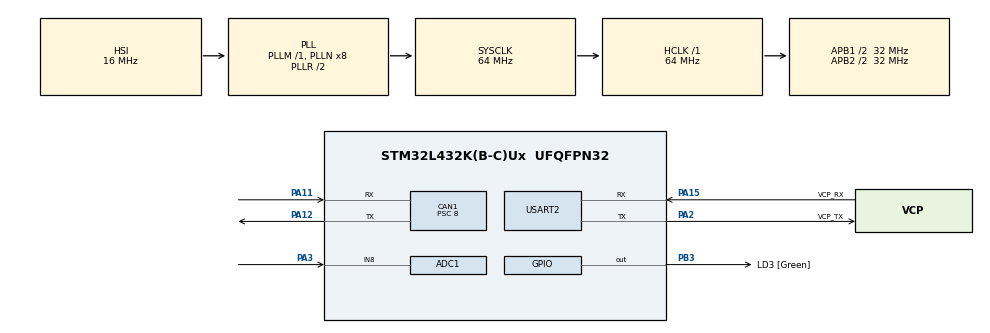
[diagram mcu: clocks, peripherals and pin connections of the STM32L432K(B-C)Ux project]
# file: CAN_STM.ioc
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ADC1.Channel-0\#ChannelRegularConversion=ADC_CHANNEL_8
ADC1.NbrOfConversionFlag=1
ADC1.OffsetNumber-0\#ChannelRegularConversion=ADC_OFFSET_NONE
ADC1.Rank-0\#ChannelRegularConversion=1
ADC1.SamplingTime-0\#ChannelRegularConversion=ADC_SAMPLETIME_2CYCLES_5
ADC1.master=1
CAN1.BS1=CAN_BS1_4TQ
CAN1.BS2=CAN_BS2_3TQ
CAN1.CalculateBaudRate=500000
CAN1.CalculateTimeBit=2000
CAN1.CalculateTimeQuantum=250.0
CAN1.Prescaler=8
Mcu.Family=STM32L4
Mcu.Name=STM32L432K(B-C)Ux
Mcu.Package=UFQFPN32
NVIC.CAN1_RX0_IRQn=true\:0\:0\:false\:false\:true\:true\:true\:true
NVIC.CAN1_RX1_IRQn=true\:0\:0\:false\:false\:true\:true\:true\:true
NVIC.PriorityGroup=NVIC_PRIORITYGROUP_4
NVIC.TIM6_DAC_IRQn=true\:0\:0\:false\:false\:true\:true\:true\:true
PA0.GPIO_Label=MCO [High speed clock in]
PA0.Mode=HSE-External-Clock-Source-for-LittleOrca
PA0.Signal=RCC_CK_IN
PA11.Mode=CAN_Activate
PA11.Signal=CAN1_RX
PA12.Mode=CAN_Activate
PA12.Signal=CAN1_TX
PA13\ (JTMS-SWDIO).GPIO_Label=SWDIO
PA13\ (JTMS-SWDIO).Mode=Serial_Wire
PA13\ (JTMS-SWDIO).Signal=SYS_JTMS-SWDIO
PA14\ (JTCK-SWCLK).GPIO_Label=SWCLK
PA14\ (JTCK-SWCLK).Mode=Serial_Wire
PA14\ (JTCK-SWCLK).Signal=SYS_JTCK-SWCLK
PA15\ (JTDI).GPIO_Label=VCP_RX
PA15\ (JTDI).Mode=Asynchronous
PA15\ (JTDI).Signal=USART2_RX
PA2.GPIO_Label=VCP_TX
PA2.Mode=Asynchronous
PA2.Signal=USART2_TX
PA3.Signal=ADCx_IN8
PB3\ (JTDO-TRACESWO).GPIO_Label=LD3 [Green]
PB3\ (JTDO-TRACESWO).Signal=GPIO_Output
PC14-OSC32_IN\ (PC14).Mode=LSE-External-Oscillator
PC14-OSC32_IN\ (PC14).Signal=RCC_OSC32_IN
PC15-OSC32_OUT\ (PC15).Mode=LSE-External-Oscillator
PC15-OSC32_OUT\ (PC15).Signal=RCC_OSC32_OUT
ProjectManager.HeapSize=0x200
ProjectManager.StackSize=0x400
ProjectManager.TargetToolchain=STM32CubeIDE
RCC.ADCFreq_Value=64000000
RCC.AHBFreq_Value=64000000
RCC.APB1CLKDivider=RCC_HCLK_DIV2
RCC.APB1Freq_Value=32000000
RCC.APB1TimFreq_Value=64000000
RCC.APB2CLKDivider=RCC_HCLK_DIV2
RCC.APB2Freq_Value=32000000
RCC.APB2TimFreq_Value=64000000
RCC.CortexFreq_Value=64000000
RCC.HCLKFreq_Value=64000000
RCC.HSE_VALUE=24000000
RCC.HSI16_VALUE=16000000
RCC.HSI48_VALUE=48000000
RCC.HSI_VALUE=16000000
RCC.MSI_VALUE=4000000
RCC.PLLMUL=RCC_PLLMUL_4
RCC.PLLSourceVirtual=RCC_PLLSOURCE_HSI
RCC.SYSCLKFreq_VALUE=64000000
RCC.SYSCLKSource=RCC_SYSCLKSOURCE_PLLCLK
RCC.USBFreq_Value=64000000
RCC.VCOOutputFreq_Value=128000000
SH.ADCx_IN8.0=ADC1_IN8,IN8-Single-Ended
TIM6.AutoReloadPreload=TIM_AUTORELOAD_PRELOAD_ENABLE
TIM6.Period=10000
TIM6.Prescaler=6400
USART2.VirtualMode-Asynchronous=VM_ASYNC
VP_TIM6_VS_ClockSourceINT.Mode=Enable_Timer
board=NUCLEO-L432KC

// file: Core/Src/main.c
/* USER CODE BEGIN Header */
/**
  ******************************************************************************
  * @file           : main.c
  * @brief          : Main program body
  ******************************************************************************
  * @attention
  *
  * Copyright (c) 2023 STMicroelectronics.
  * All rights reserved.
  *
  * This software is licensed under terms that can be found in the LICENSE file
  * in the root directory of this software component.
  * If no LICENSE file comes with this software, it is provided AS-IS.
  *
  ******************************************************************************
  */
/* USER CODE END Header */
#include "main.h"

/* USER CODE BEGIN PTD */
#include <stdio.h>
#include <string.h>
#include "mia.h"
/* USER CODE END PTD */

/* USER CODE BEGIN PD */

#define CAN_VAR_STAT
/* USER CODE END PD */

/* USER CODE BEGIN PM */

/* Private variables ---------------------------------------------------------*/
ADC_HandleTypeDef hadc1;

CAN_HandleTypeDef hcan1;

TIM_HandleTypeDef htim6;

UART_HandleTypeDef huart2;

/* USER CODE BEGIN PV */

uint16_t swap_endianness(uint16_t value) //Zrob implementacje dla inta?
{
    uint16_t ret_val;
    uint8_t lsb, msb;
    lsb = value & 0x00FF;
    msb = value & 0xFF00;
    ret_val = (lsb << 8) + (msb >> 8);

    return ret_val;

}

uint16_t asym_constraint(uint16_t value, uint16_t max)
{
    if(value > max)
    {
        return max;
    }
    else
    {
        return value;
    }
}

/* USER CODE END PM */

typedef struct __attribute__((__packed__)) stat
{
    int32_t motor_speed;
    int16_t motor_torque;
    int16_t status_word;
}stat_t;
typedef struct  __attribute__((__packed__)) CAN_EGV_Accel_VAR
{
    uint16_t accelerator_set_point;//little endian
    uint16_t regen_max;
    unsigned int forward : 1 ;
    unsigned int reverse : 1 ;
    unsigned int footbrake : 1;
    unsigned int DS1 : 1 ;
    unsigned int footswitch :1;
    unsigned int DS2 : 1;
    unsigned int unused :2;

} CAN_EGV_Accel_VAR_t;

typedef struct __attribute__((__packed__))  CAN_EGV_Cmd_VAR
{
    int16_t current_limit; //0 to 500
    int16_t regen_limit;
    uint16_t max_torque_ratio;
    uint16_t motor_command;

} CAN_EGV_Cmd_VAR_t;

typedef struct __attribute__((__packed__))  CAN_BMS_CHA
{
    int16_t charging_current; //0 to 500
    int16_t max_voltage;
    uint8_t status;

} CAN_BMS_CHA_t;

typedef struct CAN_EGV_SYNC_ALL
{
uint8_t status;

} CAN_EGV_SYNC_ALL_t;

void can_send_egv_sync_all(CAN_EGV_SYNC_ALL_t * frame)
{
    CAN_TxHeaderTypeDef carrier = {0};
    carrier.StdId = CAN_EGV_SYNC_ALL_ID;
    carrier.DLC = sizeof (CAN_EGV_SYNC_ALL_t);
    HAL_CAN_AddTxMessage(&hcan1,&carrier,(char*)frame,NULL);

}

void can_send_egv_accel_var(CAN_EGV_Accel_VAR_t * frame)
{
    CAN_TxHeaderTypeDef carrier = {0};

    carrier.StdId = CAN_EGV_ACCEL_VAR_ID;
    carrier.DLC = sizeof (CAN_EGV_Accel_VAR_t);
    //frame->accelerator_set_point = swap_endianness(frame->accelerator_set_point);
    HAL_CAN_AddTxMessage(&hcan1,&carrier,(char *)frame,NULL);
}

void can_send_egv_cmd_var(CAN_EGV_Cmd_VAR_t * frame)
{
    CAN_TxHeaderTypeDef carrier = {0};

    CAN_EGV_Cmd_VAR_t payload;

    carrier.StdId = CAN_EGV_CMD_VAR_ID;
    carrier.DLC = sizeof (CAN_EGV_Cmd_VAR_t);

    frame->regen_limit = swap_endianness(    frame->regen_limit);
    frame->max_torque_ratio = swap_endianness(frame->max_torque_ratio);
    frame->current_limit = swap_endianness(frame->current_limit);
    frame->motor_command = 0;
    frame->motor_command = swap_endianness(frame->current_limit);
    HAL_CAN_AddTxMessage(&hcan1,&carrier,(char *)&frame,NULL);

}

void can_bms_cha(CAN_BMS_CHA_t * frame)
{
    CAN_TxHeaderTypeDef carrier = {0};

    carrier.StdId = CAN_BMS_CHA_ID;
    carrier.DLC = 6;
    uint8_t crap[6];
    crap[0]=0xc8;
    crap[1]=0x00;
    crap[2]=0x88;
    crap[3]=0x13;
    crap[4]=0x03;
    crap[5]=0x00;
    //frame->accelerator_set_point = sw,ap_endianness(frame->accelerator_set_point);
    HAL_CAN_AddTxMessage(&hcan1,&carrier,(char *)frame,NULL);
}

uint16_t get_throttle()
{
    HAL_ADC_Start(&hadc1);
    uint32_t reading = HAL_ADC_GetValue(&hadc1); //0-4096
    reading = (reading>>4); //0 - 255

    if(reading > MIN_RAW_ADC_ACCEL)
    {
        reading = asym_constraint((reading-MIN_RAW_ADC_ACCEL)*250/200 + MIN_THROTTLE,MAX_RAW_ADC_ACCEL);
    }
    else
    {
        reading = 0;
    }
    return (uint16_t)reading;
}

volatile car_t mia;

void update_accel_pedal(CAN_EGV_Accel_VAR_t * frame)
{
    //int direction_forward = (HAL_GPIO_ReadPin(GPIOA, GPIO_PIN_4)== GPIO_PIN_SET);
    int direction_forward = !mia.in_reverse;

    uint16_t throttle = get_throttle();

    if(mia.var_ready && throttle >= (MIN_THROTTLE) )
    {
        frame->accelerator_set_point = throttle;
        frame->footswitch = 1; //?
        frame->unused = 0;
        frame->regen_max = 0;
        frame->footbrake =0;

        if(direction_forward)
        {
            frame->reverse = 0;
            frame->forward = 1;
        } else
        {
            frame->reverse=1;
            frame->forward = 0;
        }
    } else
    {
        frame->footswitch = 0;
        frame->forward = 0;
        frame->reverse = 0;
        frame->accelerator_set_point = 0;
    }
}

volatile CAN_EGV_Accel_VAR_t egv_accel_frame ={0};

volatile CAN_EGV_SYNC_ALL_t egv_sync_frame ={0};

volatile CAN_EGV_Cmd_VAR_t egv_var_frame ={0};

volatile CAN_BMS_CHA_t bms_cha_frame = {0};

stat_t var_stat;

void diagnostics_print()
{
    printf("Var stat: %d\nvar status %d:", var_stat.motor_speed, var_stat.status_word);
    printf("Accel frame 0x201: \n");
    printf("Accel var values %d", egv_accel_frame);
    printf("accel setpoint: %d \nfootswitch: %d \nforward: %d \n\n" ,egv_accel_frame.accelerator_set_point, egv_accel_frame.footswitch, egv_accel_frame.forward);
}

/* USER CODE END PV */
void SystemClock_Config(void);
static void MX_GPIO_Init(void);
static void MX_USART2_UART_Init(void);
static void MX_CAN1_Init(void);
static void MX_ADC1_Init(void);
static void MX_TIM6_Init(void);

/* USER CODE BEGIN 0 */
void HAL_TIM_PeriodElapsedCallback(TIM_HandleTypeDef * htim)
{

    update_accel_pedal(&egv_accel_frame);
    can_send_egv_sync_all(&egv_sync_frame);
    can_send_egv_accel_var(&egv_accel_frame);
    can_send_egv_cmd_var(&can_send_egv_cmd_var);

}

void HAL_CAN_RxFIFO0MsgPendingCallback(CAN_HandleTypeDef *hcan)
{
    //HAL_GPIO_TogglePin(LD3_GPIO_Port,LD3_Pin);
}

int __io_putchar(int ch)
{
    if (ch == '\n') {
        uint8_t ch2 = '\r';
        HAL_UART_Transmit(&huart2, &ch2, 1, HAL_MAX_DELAY);
    }

    HAL_UART_Transmit(&huart2, (uint8_t*)&ch, 1, HAL_MAX_DELAY);
    return 1;
}
/* USER CODE END 0 */

int main(void)
{

  /* MCU Configuration--------------------------------------------------------*/

  /* Reset of all peripherals, Initializes the Flash interface and the Systick. */
  HAL_Init();

  /* Configure the system clock */
  SystemClock_Config();

  /* USER CODE BEGIN SysInit */

  mia.in_reverse = 0;
  mia.reverse_button_pressed=0;
  egv_accel_frame;

  egv_accel_frame.accelerator_set_point = 0;
  egv_accel_frame.footbrake=0;
  egv_accel_frame.footswitch = 0; //?
  egv_accel_frame.regen_max = 0;
  egv_accel_frame.forward = 0;

  egv_sync_frame.status =0xff;

  egv_var_frame.current_limit = 0;
  egv_var_frame.max_torque_ratio =0;
  egv_var_frame.motor_command = 0;
  egv_var_frame.regen_limit = 0;

  bms_cha_frame.max_voltage = 8000;
  bms_cha_frame.charging_current = 550;
  bms_cha_frame.status = 1+2;
  /* USER CODE END SysInit */

  /* Initialize all configured peripherals */
  MX_GPIO_Init();
  MX_USART2_UART_Init();
  MX_CAN1_Init();
  MX_ADC1_Init();
  MX_TIM6_Init();
  /* USER CODE BEGIN 2 */

    __HAL_RCC_TIM6_CLK_ENABLE();
    HAL_TIM_Base_Start_IT(&htim6);
    HAL_NVIC_EnableIRQ(TIM6_IRQn);
    HAL_NVIC_EnableIRQ(CAN1_RX0_IRQn);

    CAN_FilterTypeDef sFilterConfig;

    sFilterConfig.FilterFIFOAssignment=CAN_FILTER_FIFO0; //set fifo assignment
    sFilterConfig.FilterIdHigh=0x181<<5; //the ID that the filter looks for (switch this for the other microcontroller)
    sFilterConfig.FilterIdLow=0;
    sFilterConfig.FilterMaskIdHigh=0;
    sFilterConfig.FilterMaskIdLow=0;
    sFilterConfig.FilterScale=CAN_FILTERSCALE_32BIT; //set filter scale
    sFilterConfig.FilterActivation=ENABLE;

    HAL_CAN_ConfigFilter(&hcan1, &sFilterConfig); //configure CAN filter

//
    HAL_CAN_Start(&hcan1);
    HAL_CAN_ActivateNotification(&hcan1, CAN_IT_RX_FIFO0_MSG_PENDING);

    __HAL_RCC_ADC_CLK_ENABLE();
    HAL_ADC_Start(&hadc1);

    HAL_Delay(1000);
    HAL_GPIO_WritePin(GPIOB,GPIO_PIN_7,GPIO_PIN_SET);
  /* USER CODE END 2 */

  /* Infinite loop */
  while (1)
  {

    /* USER CODE BEGIN 3 */
      diagnostics_print();
      if(var_stat.status_word == 1075)
    {
        mia.var_ready =1;
        egv_var_frame.current_limit = 400; //2640
        egv_var_frame.regen_limit =-20;
        egv_var_frame.max_torque_ratio =1000;
        egv_accel_frame.footswitch=1;
    }
      volatile uint8_t button_state = 0;
      if(HAL_GPIO_ReadPin(GPIOA, GPIO_PIN_4)== GPIO_PIN_RESET)
      {
          button_state = 1;
          mia.in_reverse = 1;
      }
      else
      {
          mia.in_reverse = 0;
      }
//
//      if(mia.reverse_button_pressed == 0 && button_state == 1) {
//          car_toggle_gear(&mia);
//         // mia.reverse_button_pressed = !mia.reverse_button_pressed;
//         mia.reverse_button_pressed = 1;
//      }
//      if(button_state == 0)
//      {
//          mia.reverse_button_pressed = 0;
//      }
//      if(button_state == 1)
//      {
//          mia.reverse_button_pressed =1;
//      }

     HAL_Delay(1000);
      HAL_GPIO_TogglePin(LD3_GPIO_Port,LD3_Pin);
      can_bms_cha(&bms_cha_frame);
      printf("%d \n",egv_accel_frame.accelerator_set_point);

  }
  /* USER CODE END 3 */

}

void SystemClock_Config(void)
{
  RCC_OscInitTypeDef RCC_OscInitStruct = {0};
  RCC_ClkInitTypeDef RCC_ClkInitStruct = {0};

  /** Configure the main internal regulator output voltage
  */
  if (HAL_PWREx_ControlVoltageScaling(PWR_REGULATOR_VOLTAGE_SCALE1) != HAL_OK)
  {
    Error_Handler();
  }

  /** Initializes the RCC Oscillators according to the specified parameters
  * in the RCC_OscInitTypeDef structure.
  */
  RCC_OscInitStruct.OscillatorType = RCC_OSCILLATORTYPE_HSI;
  RCC_OscInitStruct.HSIState = RCC_HSI_ON;
  RCC_OscInitStruct.HSICalibrationValue = RCC_HSICALIBRATION_DEFAULT;
  RCC_OscInitStruct.PLL.PLLState = RCC_PLL_ON;
  RCC_OscInitStruct.PLL.PLLSource = RCC_PLLSOURCE_HSI;
  RCC_OscInitStruct.PLL.PLLM = 1;
  RCC_OscInitStruct.PLL.PLLN = 8;
  RCC_OscInitStruct.PLL.PLLP = RCC_PLLP_DIV7;
  RCC_OscInitStruct.PLL.PLLQ = RCC_PLLQ_DIV2;
  RCC_OscInitStruct.PLL.PLLR = RCC_PLLR_DIV2;
  if (HAL_RCC_OscConfig(&RCC_OscInitStruct) != HAL_OK)
  {
    Error_Handler();
  }

  /** Initializes the CPU, AHB and APB buses clocks
  */
  RCC_ClkInitStruct.ClockType = RCC_CLOCKTYPE_HCLK|RCC_CLOCKTYPE_SYSCLK
                              |RCC_CLOCKTYPE_PCLK1|RCC_CLOCKTYPE_PCLK2;
  RCC_ClkInitStruct.SYSCLKSource = RCC_SYSCLKSOURCE_PLLCLK;
  RCC_ClkInitStruct.AHBCLKDivider = RCC_SYSCLK_DIV1;
  RCC_ClkInitStruct.APB1CLKDivider = RCC_HCLK_DIV2;
  RCC_ClkInitStruct.APB2CLKDivider = RCC_HCLK_DIV2;

  if (HAL_RCC_ClockConfig(&RCC_ClkInitStruct, FLASH_LATENCY_3) != HAL_OK)
  {
    Error_Handler();
  }
}

static void MX_ADC1_Init(void)
{

  ADC_ChannelConfTypeDef sConfig = {0};

  /** Common config
  */
  hadc1.Instance = ADC1;
  hadc1.Init.ClockPrescaler = ADC_CLOCK_ASYNC_DIV1;
  hadc1.Init.Resolution = ADC_RESOLUTION_12B;
  hadc1.Init.DataAlign = ADC_DATAALIGN_RIGHT;
  hadc1.Init.ScanConvMode = ADC_SCAN_DISABLE;
  hadc1.Init.EOCSelection = ADC_EOC_SINGLE_CONV;
  hadc1.Init.LowPowerAutoWait = DISABLE;
  hadc1.Init.ContinuousConvMode = DISABLE;
  hadc1.Init.NbrOfConversion = 1;
  hadc1.Init.DiscontinuousConvMode = DISABLE;
  hadc1.Init.ExternalTrigConv = ADC_SOFTWARE_START;
  hadc1.Init.ExternalTrigConvEdge = ADC_EXTERNALTRIGCONVEDGE_NONE;
  hadc1.Init.DMAContinuousRequests = DISABLE;
  hadc1.Init.Overrun = ADC_OVR_DATA_PRESERVED;
  hadc1.Init.OversamplingMode = DISABLE;
  if (HAL_ADC_Init(&hadc1) != HAL_OK)
  {
    Error_Handler();
  }

  /** Configure Regular Channel
  */
  sConfig.Channel = ADC_CHANNEL_8;
  sConfig.Rank = ADC_REGULAR_RANK_1;
  sConfig.SamplingTime = ADC_SAMPLETIME_2CYCLES_5;
  sConfig.SingleDiff = ADC_SINGLE_ENDED;
  sConfig.OffsetNumber = ADC_OFFSET_NONE;
  sConfig.Offset = 0;
  if (HAL_ADC_ConfigChannel(&hadc1, &sConfig) != HAL_OK)
  {
    Error_Handler();
  }

}

static void MX_CAN1_Init(void)
{

  hcan1.Instance = CAN1;
  hcan1.Init.Prescaler = 4;
  hcan1.Init.Mode = CAN_MODE_NORMAL;
  hcan1.Init.SyncJumpWidth = CAN_SJW_1TQ;
  hcan1.Init.TimeSeg1 = CAN_BS1_12TQ;
  hcan1.Init.TimeSeg2 = CAN_BS2_3TQ;
  hcan1.Init.TimeTriggeredMode = DISABLE;
  hcan1.Init.AutoBusOff = DISABLE;
  hcan1.Init.AutoWakeUp = DISABLE;
  hcan1.Init.AutoRetransmission = DISABLE;
  hcan1.Init.ReceiveFifoLocked = DISABLE;
  hcan1.Init.TransmitFifoPriority = DISABLE;
  if (HAL_CAN_Init(&hcan1) != HAL_OK)
  {
    Error_Handler();
  }

}

static void MX_TIM6_Init(void)
{

  TIM_MasterConfigTypeDef sMasterConfig = {0};

  htim6.Instance = TIM6;
  htim6.Init.Prescaler = 6400;
  htim6.Init.CounterMode = TIM_COUNTERMODE_UP;
  htim6.Init.Period = 100; // every 10ms
  htim6.Init.AutoReloadPreload = TIM_AUTORELOAD_PRELOAD_ENABLE;
  if (HAL_TIM_Base_Init(&htim6) != HAL_OK)
  {
    Error_Handler();
  }
  sMasterConfig.MasterOutputTrigger = TIM_TRGO_RESET;
  sMasterConfig.MasterSlaveMode = TIM_MASTERSLAVEMODE_DISABLE;
  if (HAL_TIMEx_MasterConfigSynchronization(&htim6, &sMasterConfig) != HAL_OK)
  {
    Error_Handler();
  }

}

static void MX_USART2_UART_Init(void)
{

  huart2.Instance = USART2;
  huart2.Init.BaudRate = 115200;
  huart2.Init.WordLength = UART_WORDLENGTH_8B;
  huart2.Init.StopBits = UART_STOPBITS_1;
  huart2.Init.Parity = UART_PARITY_NONE;
  huart2.Init.Mode = UART_MODE_TX_RX;
  huart2.Init.HwFlowCtl = UART_HWCONTROL_NONE;
  huart2.Init.OverSampling = UART_OVERSAMPLING_16;
  huart2.Init.OneBitSampling = UART_ONE_BIT_SAMPLE_DISABLE;
  huart2.AdvancedInit.AdvFeatureInit = UART_ADVFEATURE_NO_INIT;
  if (HAL_UART_Init(&huart2) != HAL_OK)
  {
    Error_Handler();
  }

}

static void MX_GPIO_Init(void)
{
  GPIO_InitTypeDef GPIO_InitStruct = {0};

  /* GPIO Ports Clock Enable */
  __HAL_RCC_GPIOC_CLK_ENABLE();
  __HAL_RCC_GPIOA_CLK_ENABLE();
  __HAL_RCC_GPIOB_CLK_ENABLE();

  /*Configure GPIO pin Output Level */
  HAL_GPIO_WritePin(LD3_GPIO_Port, LD3_Pin, GPIO_PIN_RESET);

  /*Configure GPIO pin : LD3_Pin */
  GPIO_InitStruct.Pin = LD3_Pin;
  GPIO_InitStruct.Mode = GPIO_MODE_OUTPUT_PP;
  GPIO_InitStruct.Pull = GPIO_NOPULL;
  GPIO_InitStruct.Speed = GPIO_SPEED_FREQ_LOW;
  HAL_GPIO_Init(LD3_GPIO_Port, &GPIO_InitStruct);

  GPIO_InitStruct.Pin = GPIO_PIN_4;
  GPIO_InitStruct.Mode = GPIO_MODE_INPUT;
  GPIO_InitStruct.Pull = GPIO_PULLUP;
  GPIO_InitStruct.Speed = GPIO_SPEED_FREQ_LOW;
    HAL_GPIO_Init(GPIOA, &GPIO_InitStruct);

    GPIO_InitStruct.Pin = GPIO_PIN_7;
    GPIO_InitStruct.Mode = GPIO_MODE_OUTPUT_PP;
    GPIO_InitStruct.Pull = GPIO_NOPULL;
    GPIO_InitStruct.Speed = GPIO_SPEED_FREQ_LOW;
    HAL_GPIO_Init(GPIOB, &GPIO_InitStruct);

}

void Error_Handler(void)
{
  __disable_irq();
  while (1)
  {
  }
}
